VERSION 5.8 ;
BUSBITCHARS "[]" ;
DIVIDERCHAR "/" ;
UNITS
  DATABASE MICRONS 1000 ;
END UNITS
MANUFACTURINGGRID 0.005 ;

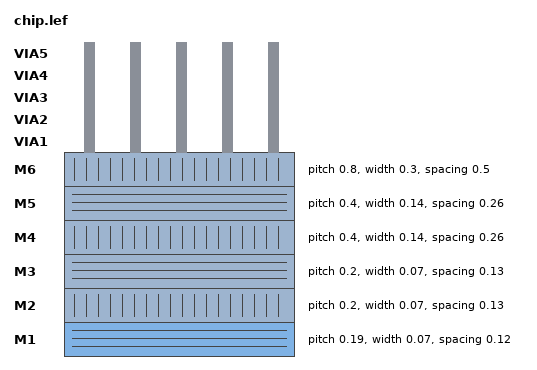
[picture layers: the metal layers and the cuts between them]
LAYER M1
  TYPE ROUTING ;
  DIRECTION HORIZONTAL ;
  PITCH 0.19 ;
  WIDTH 0.07 ;
  SPACING 0.12 ;
END M1

LAYER M2
  TYPE ROUTING ;
  DIRECTION VERTICAL ;
  PITCH 0.2 ;
  WIDTH 0.07 ;
  SPACING 0.13 ;
END M2

LAYER M3
  TYPE ROUTING ;
  DIRECTION HORIZONTAL ;
  PITCH 0.2 ;
  WIDTH 0.07 ;
  SPACING 0.13 ;
END M3

LAYER M4
  TYPE ROUTING ;
  DIRECTION VERTICAL ;
  PITCH 0.4 ;
  WIDTH 0.14 ;
  SPACING 0.26 ;
END M4

LAYER M5
  TYPE ROUTING ;
  DIRECTION HORIZONTAL ;
  PITCH 0.4 ;
  WIDTH 0.14 ;
  SPACING 0.26 ;
END M5

LAYER M6
  TYPE ROUTING ;
  DIRECTION VERTICAL ;
  PITCH 0.8 ;
  WIDTH 0.3 ;
  SPACING 0.5 ;
END M6

LAYER VIA1
  TYPE CUT ;
END VIA1

LAYER VIA2
  TYPE CUT ;
END VIA2

LAYER VIA3
  TYPE CUT ;
END VIA3

LAYER VIA4
  TYPE CUT ;
END VIA4

LAYER VIA5
  TYPE CUT ;
END VIA5

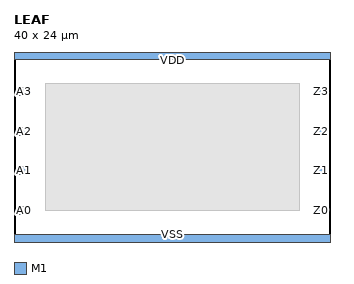
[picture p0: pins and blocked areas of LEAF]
MACRO LEAF
  CLASS CORE ;
  ORIGIN 0 0 ;
  SIZE 40 BY 24 ;
  SYMMETRY X Y ;
  PIN A0
    DIRECTION INPUT ;
    USE SIGNAL ;
    PORT
      LAYER M1 ;
      RECT 0.5 3.5 1.5 4.5 ;
    END
  END A0
  PIN A1
    DIRECTION INPUT ;
    USE SIGNAL ;
    PORT
      LAYER M1 ;
      RECT 0.5 8.5 1.5 9.5 ;
    END
  END A1
  PIN A2
    DIRECTION INPUT ;
    USE SIGNAL ;
    PORT
      LAYER M1 ;
      RECT 0.5 13.5 1.5 14.5 ;
    END
  END A2
  PIN A3
    DIRECTION INPUT ;
    USE SIGNAL ;
    PORT
      LAYER M1 ;
      RECT 0.5 18.5 1.5 19.5 ;
    END
  END A3
  PIN Z0
    DIRECTION OUTPUT ;
    USE SIGNAL ;
    PORT
      LAYER M1 ;
      RECT 38.5 3.5 39.5 4.5 ;
    END
  END Z0
  PIN Z1
    DIRECTION OUTPUT ;
    USE SIGNAL ;
    PORT
      LAYER M1 ;
      RECT 38.5 8.5 39.5 9.5 ;
    END
  END Z1
  PIN Z2
    DIRECTION OUTPUT ;
    USE SIGNAL ;
    PORT
      LAYER M1 ;
      RECT 38.5 13.5 39.5 14.5 ;
    END
  END Z2
  PIN Z3
    DIRECTION OUTPUT ;
    USE SIGNAL ;
    PORT
      LAYER M1 ;
      RECT 38.5 18.5 39.5 19.5 ;
    END
  END Z3
  PIN VDD
    DIRECTION INOUT ;
    USE POWER ;
    PORT
      LAYER M1 ;
      RECT 0 23 40 24 ;
    END
  END VDD
  PIN VSS
    DIRECTION INOUT ;
    USE GROUND ;
    PORT
      LAYER M1 ;
      RECT 0 0 40 1 ;
    END
  END VSS
  OBS
    LAYER M2 ;
    RECT 4 4 36 20 ;
  END
END LEAF

END LIBRARY
